VERSION 5.8 ;
BUSBITCHARS "[]" ;
DIVIDERCHAR "/" ;
UNITS
    DATABASE MICRONS 1000 ;
END UNITS

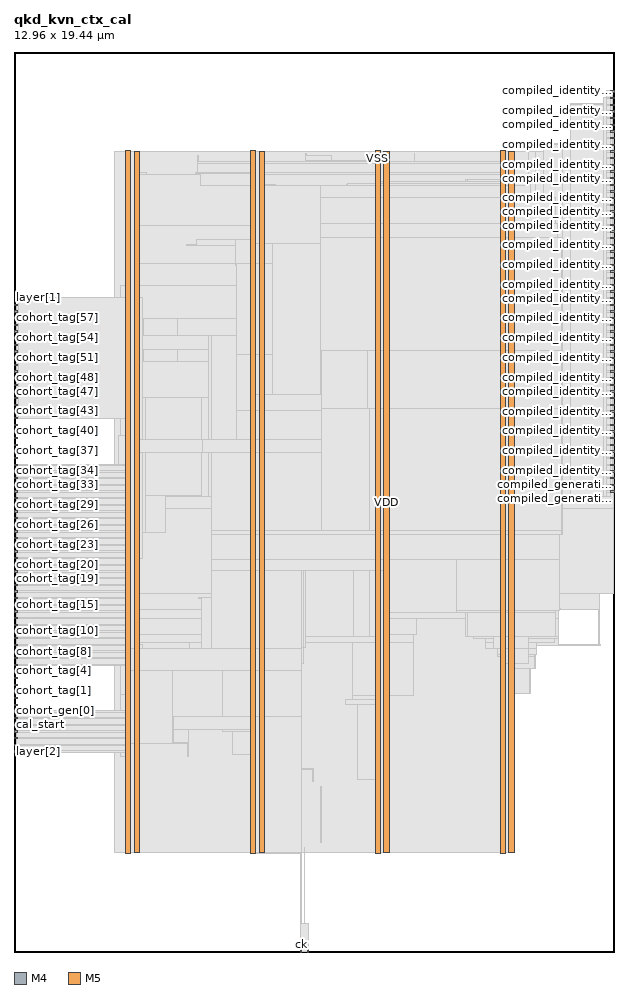
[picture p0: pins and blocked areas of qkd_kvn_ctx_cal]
MACRO qkd_kvn_ctx_cal
  FOREIGN qkd_kvn_ctx_cal 0 0 ;
  CLASS BLOCK ;
  SIZE 12.96 BY 19.44 ;
  PIN cal_start
    DIRECTION INPUT ;
    USE SIGNAL ;
    PORT
      LAYER M4 ;
        RECT  0 4.896 0.084 4.92 ;
    END
  END cal_start
  PIN ck
    DIRECTION INPUT ;
    USE SIGNAL ;
    PORT
      LAYER M5 ;
        RECT  6.192 0 6.216 0.084 ;
    END
  END ck
  PIN cohort_gen[0]
    DIRECTION INPUT ;
    USE SIGNAL ;
    PORT
      LAYER M4 ;
        RECT  0 5.04 0.084 5.064 ;
    END
  END cohort_gen[0]
  PIN cohort_gen[1]
    DIRECTION INPUT ;
    USE SIGNAL ;
    PORT
      LAYER M4 ;
        RECT  0 5.184 0.084 5.208 ;
    END
  END cohort_gen[1]
  PIN cohort_tag[0]
    DIRECTION INPUT ;
    USE SIGNAL ;
    PORT
      LAYER M4 ;
        RECT  0 5.328 0.084 5.352 ;
    END
  END cohort_tag[0]
  PIN cohort_tag[10]
    DIRECTION INPUT ;
    USE SIGNAL ;
    PORT
      LAYER M4 ;
        RECT  0 6.768 0.084 6.792 ;
    END
  END cohort_tag[10]
  PIN cohort_tag[11]
    DIRECTION INPUT ;
    USE SIGNAL ;
    PORT
      LAYER M4 ;
        RECT  0 6.912 0.084 6.936 ;
    END
  END cohort_tag[11]
  PIN cohort_tag[12]
    DIRECTION INPUT ;
    USE SIGNAL ;
    PORT
      LAYER M4 ;
        RECT  0 7.056 0.084 7.08 ;
    END
  END cohort_tag[12]
  PIN cohort_tag[13]
    DIRECTION INPUT ;
    USE SIGNAL ;
    PORT
      LAYER M4 ;
        RECT  0 7.2 0.084 7.224 ;
    END
  END cohort_tag[13]
  PIN cohort_tag[14]
    DIRECTION INPUT ;
    USE SIGNAL ;
    PORT
      LAYER M4 ;
        RECT  0 7.344 0.084 7.368 ;
    END
  END cohort_tag[14]
  PIN cohort_tag[15]
    DIRECTION INPUT ;
    USE SIGNAL ;
    PORT
      LAYER M4 ;
        RECT  0 7.488 0.084 7.512 ;
    END
  END cohort_tag[15]
  PIN cohort_tag[16]
    DIRECTION INPUT ;
    USE SIGNAL ;
    PORT
      LAYER M4 ;
        RECT  0 7.632 0.084 7.656 ;
    END
  END cohort_tag[16]
  PIN cohort_tag[17]
    DIRECTION INPUT ;
    USE SIGNAL ;
    PORT
      LAYER M4 ;
        RECT  0 7.776 0.084 7.8 ;
    END
  END cohort_tag[17]
  PIN cohort_tag[18]
    DIRECTION INPUT ;
    USE SIGNAL ;
    PORT
      LAYER M4 ;
        RECT  0 7.92 0.084 7.944 ;
    END
  END cohort_tag[18]
  PIN cohort_tag[19]
    DIRECTION INPUT ;
    USE SIGNAL ;
    PORT
      LAYER M4 ;
        RECT  0 8.064 0.084 8.088 ;
    END
  END cohort_tag[19]
  PIN cohort_tag[1]
    DIRECTION INPUT ;
    USE SIGNAL ;
    PORT
      LAYER M4 ;
        RECT  0 5.472 0.084 5.496 ;
    END
  END cohort_tag[1]
  PIN cohort_tag[20]
    DIRECTION INPUT ;
    USE SIGNAL ;
    PORT
      LAYER M4 ;
        RECT  0 8.208 0.084 8.232 ;
    END
  END cohort_tag[20]
  PIN cohort_tag[21]
    DIRECTION INPUT ;
    USE SIGNAL ;
    PORT
      LAYER M4 ;
        RECT  0 8.352 0.084 8.376 ;
    END
  END cohort_tag[21]
  PIN cohort_tag[22]
    DIRECTION INPUT ;
    USE SIGNAL ;
    PORT
      LAYER M4 ;
        RECT  0 8.496 0.084 8.52 ;
    END
  END cohort_tag[22]
  PIN cohort_tag[23]
    DIRECTION INPUT ;
    USE SIGNAL ;
    PORT
      LAYER M4 ;
        RECT  0 8.64 0.084 8.664 ;
    END
  END cohort_tag[23]
  PIN cohort_tag[24]
    DIRECTION INPUT ;
    USE SIGNAL ;
    PORT
      LAYER M4 ;
        RECT  0 8.784 0.084 8.808 ;
    END
  END cohort_tag[24]
  PIN cohort_tag[25]
    DIRECTION INPUT ;
    USE SIGNAL ;
    PORT
      LAYER M4 ;
        RECT  0 8.928 0.084 8.952 ;
    END
  END cohort_tag[25]
  PIN cohort_tag[26]
    DIRECTION INPUT ;
    USE SIGNAL ;
    PORT
      LAYER M4 ;
        RECT  0 9.072 0.084 9.096 ;
    END
  END cohort_tag[26]
  PIN cohort_tag[27]
    DIRECTION INPUT ;
    USE SIGNAL ;
    PORT
      LAYER M4 ;
        RECT  0 9.216 0.084 9.24 ;
    END
  END cohort_tag[27]
  PIN cohort_tag[28]
    DIRECTION INPUT ;
    USE SIGNAL ;
    PORT
      LAYER M4 ;
        RECT  0 9.36 0.084 9.384 ;
    END
  END cohort_tag[28]
  PIN cohort_tag[29]
    DIRECTION INPUT ;
    USE SIGNAL ;
    PORT
      LAYER M4 ;
        RECT  0 9.504 0.084 9.528 ;
    END
  END cohort_tag[29]
  PIN cohort_tag[2]
    DIRECTION INPUT ;
    USE SIGNAL ;
    PORT
      LAYER M4 ;
        RECT  0 5.616 0.084 5.64 ;
    END
  END cohort_tag[2]
  PIN cohort_tag[30]
    DIRECTION INPUT ;
    USE SIGNAL ;
    PORT
      LAYER M4 ;
        RECT  0 9.648 0.084 9.672 ;
    END
  END cohort_tag[30]
  PIN cohort_tag[31]
    DIRECTION INPUT ;
    USE SIGNAL ;
    PORT
      LAYER M4 ;
        RECT  0 9.792 0.084 9.816 ;
    END
  END cohort_tag[31]
  PIN cohort_tag[32]
    DIRECTION INPUT ;
    USE SIGNAL ;
    PORT
      LAYER M4 ;
        RECT  0 9.936 0.084 9.96 ;
    END
  END cohort_tag[32]
  PIN cohort_tag[33]
    DIRECTION INPUT ;
    USE SIGNAL ;
    PORT
      LAYER M4 ;
        RECT  0 10.08 0.084 10.104 ;
    END
  END cohort_tag[33]
  PIN cohort_tag[34]
    DIRECTION INPUT ;
    USE SIGNAL ;
    PORT
      LAYER M4 ;
        RECT  0 10.224 0.084 10.248 ;
    END
  END cohort_tag[34]
  PIN cohort_tag[35]
    DIRECTION INPUT ;
    USE SIGNAL ;
    PORT
      LAYER M4 ;
        RECT  0 10.368 0.084 10.392 ;
    END
  END cohort_tag[35]
  PIN cohort_tag[36]
    DIRECTION INPUT ;
    USE SIGNAL ;
    PORT
      LAYER M4 ;
        RECT  0 10.512 0.084 10.536 ;
    END
  END cohort_tag[36]
  PIN cohort_tag[37]
    DIRECTION INPUT ;
    USE SIGNAL ;
    PORT
      LAYER M4 ;
        RECT  0 10.656 0.084 10.68 ;
    END
  END cohort_tag[37]
  PIN cohort_tag[38]
    DIRECTION INPUT ;
    USE SIGNAL ;
    PORT
      LAYER M4 ;
        RECT  0 10.8 0.084 10.824 ;
    END
  END cohort_tag[38]
  PIN cohort_tag[39]
    DIRECTION INPUT ;
    USE SIGNAL ;
    PORT
      LAYER M4 ;
        RECT  0 10.944 0.084 10.968 ;
    END
  END cohort_tag[39]
  PIN cohort_tag[3]
    DIRECTION INPUT ;
    USE SIGNAL ;
    PORT
      LAYER M4 ;
        RECT  0 5.76 0.084 5.784 ;
    END
  END cohort_tag[3]
  PIN cohort_tag[40]
    DIRECTION INPUT ;
    USE SIGNAL ;
    PORT
      LAYER M4 ;
        RECT  0 11.088 0.084 11.112 ;
    END
  END cohort_tag[40]
  PIN cohort_tag[41]
    DIRECTION INPUT ;
    USE SIGNAL ;
    PORT
      LAYER M4 ;
        RECT  0 11.232 0.084 11.256 ;
    END
  END cohort_tag[41]
  PIN cohort_tag[42]
    DIRECTION INPUT ;
    USE SIGNAL ;
    PORT
      LAYER M4 ;
        RECT  0 11.376 0.084 11.4 ;
    END
  END cohort_tag[42]
  PIN cohort_tag[43]
    DIRECTION INPUT ;
    USE SIGNAL ;
    PORT
      LAYER M4 ;
        RECT  0 11.52 0.084 11.544 ;
    END
  END cohort_tag[43]
  PIN cohort_tag[44]
    DIRECTION INPUT ;
    USE SIGNAL ;
    PORT
      LAYER M4 ;
        RECT  0 11.664 0.084 11.688 ;
    END
  END cohort_tag[44]
  PIN cohort_tag[45]
    DIRECTION INPUT ;
    USE SIGNAL ;
    PORT
      LAYER M4 ;
        RECT  0 11.808 0.084 11.832 ;
    END
  END cohort_tag[45]
  PIN cohort_tag[46]
    DIRECTION INPUT ;
    USE SIGNAL ;
    PORT
      LAYER M4 ;
        RECT  0 11.952 0.084 11.976 ;
    END
  END cohort_tag[46]
  PIN cohort_tag[47]
    DIRECTION INPUT ;
    USE SIGNAL ;
    PORT
      LAYER M4 ;
        RECT  0 12.096 0.084 12.12 ;
    END
  END cohort_tag[47]
  PIN cohort_tag[48]
    DIRECTION INPUT ;
    USE SIGNAL ;
    PORT
      LAYER M4 ;
        RECT  0 12.24 0.084 12.264 ;
    END
  END cohort_tag[48]
  PIN cohort_tag[49]
    DIRECTION INPUT ;
    USE SIGNAL ;
    PORT
      LAYER M4 ;
        RECT  0 12.384 0.084 12.408 ;
    END
  END cohort_tag[49]
  PIN cohort_tag[4]
    DIRECTION INPUT ;
    USE SIGNAL ;
    PORT
      LAYER M4 ;
        RECT  0 5.904 0.084 5.928 ;
    END
  END cohort_tag[4]
  PIN cohort_tag[50]
    DIRECTION INPUT ;
    USE SIGNAL ;
    PORT
      LAYER M4 ;
        RECT  0 12.528 0.084 12.552 ;
    END
  END cohort_tag[50]
  PIN cohort_tag[51]
    DIRECTION INPUT ;
    USE SIGNAL ;
    PORT
      LAYER M4 ;
        RECT  0 12.672 0.084 12.696 ;
    END
  END cohort_tag[51]
  PIN cohort_tag[52]
    DIRECTION INPUT ;
    USE SIGNAL ;
    PORT
      LAYER M4 ;
        RECT  0 12.816 0.084 12.84 ;
    END
  END cohort_tag[52]
  PIN cohort_tag[53]
    DIRECTION INPUT ;
    USE SIGNAL ;
    PORT
      LAYER M4 ;
        RECT  0 12.96 0.084 12.984 ;
    END
  END cohort_tag[53]
  PIN cohort_tag[54]
    DIRECTION INPUT ;
    USE SIGNAL ;
    PORT
      LAYER M4 ;
        RECT  0 13.104 0.084 13.128 ;
    END
  END cohort_tag[54]
  PIN cohort_tag[55]
    DIRECTION INPUT ;
    USE SIGNAL ;
    PORT
      LAYER M4 ;
        RECT  0 13.248 0.084 13.272 ;
    END
  END cohort_tag[55]
  PIN cohort_tag[56]
    DIRECTION INPUT ;
    USE SIGNAL ;
    PORT
      LAYER M4 ;
        RECT  0 13.392 0.084 13.416 ;
    END
  END cohort_tag[56]
  PIN cohort_tag[57]
    DIRECTION INPUT ;
    USE SIGNAL ;
    PORT
      LAYER M4 ;
        RECT  0 13.536 0.084 13.56 ;
    END
  END cohort_tag[57]
  PIN cohort_tag[58]
    DIRECTION INPUT ;
    USE SIGNAL ;
    PORT
      LAYER M4 ;
        RECT  0 13.68 0.084 13.704 ;
    END
  END cohort_tag[58]
  PIN cohort_tag[5]
    DIRECTION INPUT ;
    USE SIGNAL ;
    PORT
      LAYER M4 ;
        RECT  0 6.048 0.084 6.072 ;
    END
  END cohort_tag[5]
  PIN cohort_tag[6]
    DIRECTION INPUT ;
    USE SIGNAL ;
    PORT
      LAYER M4 ;
        RECT  0 6.192 0.084 6.216 ;
    END
  END cohort_tag[6]
  PIN cohort_tag[7]
    DIRECTION INPUT ;
    USE SIGNAL ;
    PORT
      LAYER M4 ;
        RECT  0 6.336 0.084 6.36 ;
    END
  END cohort_tag[7]
  PIN cohort_tag[8]
    DIRECTION INPUT ;
    USE SIGNAL ;
    PORT
      LAYER M4 ;
        RECT  0 6.48 0.084 6.504 ;
    END
  END cohort_tag[8]
  PIN cohort_tag[9]
    DIRECTION INPUT ;
    USE SIGNAL ;
    PORT
      LAYER M4 ;
        RECT  0 6.624 0.084 6.648 ;
    END
  END cohort_tag[9]
  PIN compiled_generation[0]
    DIRECTION OUTPUT ;
    USE SIGNAL ;
    PORT
      LAYER M4 ;
        RECT  12.876 9.936 12.96 9.96 ;
    END
  END compiled_generation[0]
  PIN compiled_generation[1]
    DIRECTION OUTPUT ;
    USE SIGNAL ;
    PORT
      LAYER M4 ;
        RECT  12.876 10.08 12.96 10.104 ;
    END
  END compiled_generation[1]
  PIN compiled_identity[0]
    DIRECTION OUTPUT ;
    USE SIGNAL ;
    PORT
      LAYER M4 ;
        RECT  12.876 10.224 12.96 10.248 ;
    END
  END compiled_identity[0]
  PIN compiled_identity[10]
    DIRECTION OUTPUT ;
    USE SIGNAL ;
    PORT
      LAYER M4 ;
        RECT  12.876 11.664 12.96 11.688 ;
    END
  END compiled_identity[10]
  PIN compiled_identity[11]
    DIRECTION OUTPUT ;
    USE SIGNAL ;
    PORT
      LAYER M4 ;
        RECT  12.876 11.808 12.96 11.832 ;
    END
  END compiled_identity[11]
  PIN compiled_identity[12]
    DIRECTION OUTPUT ;
    USE SIGNAL ;
    PORT
      LAYER M4 ;
        RECT  12.876 11.952 12.96 11.976 ;
    END
  END compiled_identity[12]
  PIN compiled_identity[13]
    DIRECTION OUTPUT ;
    USE SIGNAL ;
    PORT
      LAYER M4 ;
        RECT  12.876 12.096 12.96 12.12 ;
    END
  END compiled_identity[13]
  PIN compiled_identity[14]
    DIRECTION OUTPUT ;
    USE SIGNAL ;
    PORT
      LAYER M4 ;
        RECT  12.876 12.24 12.96 12.264 ;
    END
  END compiled_identity[14]
  PIN compiled_identity[15]
    DIRECTION OUTPUT ;
    USE SIGNAL ;
    PORT
      LAYER M4 ;
        RECT  12.876 12.384 12.96 12.408 ;
    END
  END compiled_identity[15]
  PIN compiled_identity[16]
    DIRECTION OUTPUT ;
    USE SIGNAL ;
    PORT
      LAYER M4 ;
        RECT  12.876 12.528 12.96 12.552 ;
    END
  END compiled_identity[16]
  PIN compiled_identity[17]
    DIRECTION OUTPUT ;
    USE SIGNAL ;
    PORT
      LAYER M4 ;
        RECT  12.876 12.672 12.96 12.696 ;
    END
  END compiled_identity[17]
  PIN compiled_identity[18]
    DIRECTION OUTPUT ;
    USE SIGNAL ;
    PORT
      LAYER M4 ;
        RECT  12.876 12.816 12.96 12.84 ;
    END
  END compiled_identity[18]
  PIN compiled_identity[19]
    DIRECTION OUTPUT ;
    USE SIGNAL ;
    PORT
      LAYER M4 ;
        RECT  12.876 12.96 12.96 12.984 ;
    END
  END compiled_identity[19]
  PIN compiled_identity[1]
    DIRECTION OUTPUT ;
    USE SIGNAL ;
    PORT
      LAYER M4 ;
        RECT  12.876 10.368 12.96 10.392 ;
    END
  END compiled_identity[1]
  PIN compiled_identity[20]
    DIRECTION OUTPUT ;
    USE SIGNAL ;
    PORT
      LAYER M4 ;
        RECT  12.876 13.104 12.96 13.128 ;
    END
  END compiled_identity[20]
  PIN compiled_identity[21]
    DIRECTION OUTPUT ;
    USE SIGNAL ;
    PORT
      LAYER M4 ;
        RECT  12.876 13.248 12.96 13.272 ;
    END
  END compiled_identity[21]
  PIN compiled_identity[22]
    DIRECTION OUTPUT ;
    USE SIGNAL ;
    PORT
      LAYER M4 ;
        RECT  12.876 13.392 12.96 13.416 ;
    END
  END compiled_identity[22]
  PIN compiled_identity[23]
    DIRECTION OUTPUT ;
    USE SIGNAL ;
    PORT
      LAYER M4 ;
        RECT  12.876 13.536 12.96 13.56 ;
    END
  END compiled_identity[23]
  PIN compiled_identity[24]
    DIRECTION OUTPUT ;
    USE SIGNAL ;
    PORT
      LAYER M4 ;
        RECT  12.876 13.68 12.96 13.704 ;
    END
  END compiled_identity[24]
  PIN compiled_identity[25]
    DIRECTION OUTPUT ;
    USE SIGNAL ;
    PORT
      LAYER M4 ;
        RECT  12.876 13.824 12.96 13.848 ;
    END
  END compiled_identity[25]
  PIN compiled_identity[26]
    DIRECTION OUTPUT ;
    USE SIGNAL ;
    PORT
      LAYER M4 ;
        RECT  12.876 13.968 12.96 13.992 ;
    END
  END compiled_identity[26]
  PIN compiled_identity[27]
    DIRECTION OUTPUT ;
    USE SIGNAL ;
    PORT
      LAYER M4 ;
        RECT  12.876 14.112 12.96 14.136 ;
    END
  END compiled_identity[27]
  PIN compiled_identity[28]
    DIRECTION OUTPUT ;
    USE SIGNAL ;
    PORT
      LAYER M4 ;
        RECT  12.876 14.256 12.96 14.28 ;
    END
  END compiled_identity[28]
  PIN compiled_identity[29]
    DIRECTION OUTPUT ;
    USE SIGNAL ;
    PORT
      LAYER M4 ;
        RECT  12.876 14.4 12.96 14.424 ;
    END
  END compiled_identity[29]
  PIN compiled_identity[2]
    DIRECTION OUTPUT ;
    USE SIGNAL ;
    PORT
      LAYER M4 ;
        RECT  12.876 10.512 12.96 10.536 ;
    END
  END compiled_identity[2]
  PIN compiled_identity[30]
    DIRECTION OUTPUT ;
    USE SIGNAL ;
    PORT
      LAYER M4 ;
        RECT  12.876 14.544 12.96 14.568 ;
    END
  END compiled_identity[30]
  PIN compiled_identity[31]
    DIRECTION OUTPUT ;
    USE SIGNAL ;
    PORT
      LAYER M4 ;
        RECT  12.876 14.688 12.96 14.712 ;
    END
  END compiled_identity[31]
  PIN compiled_identity[32]
    DIRECTION OUTPUT ;
    USE SIGNAL ;
    PORT
      LAYER M4 ;
        RECT  12.876 14.832 12.96 14.856 ;
    END
  END compiled_identity[32]
  PIN compiled_identity[33]
    DIRECTION OUTPUT ;
    USE SIGNAL ;
    PORT
      LAYER M4 ;
        RECT  12.876 14.976 12.96 15 ;
    END
  END compiled_identity[33]
  PIN compiled_identity[34]
    DIRECTION OUTPUT ;
    USE SIGNAL ;
    PORT
      LAYER M4 ;
        RECT  12.876 15.12 12.96 15.144 ;
    END
  END compiled_identity[34]
  PIN compiled_identity[35]
    DIRECTION OUTPUT ;
    USE SIGNAL ;
    PORT
      LAYER M4 ;
        RECT  12.876 15.264 12.96 15.288 ;
    END
  END compiled_identity[35]
  PIN compiled_identity[36]
    DIRECTION OUTPUT ;
    USE SIGNAL ;
    PORT
      LAYER M4 ;
        RECT  12.876 15.408 12.96 15.432 ;
    END
  END compiled_identity[36]
  PIN compiled_identity[37]
    DIRECTION OUTPUT ;
    USE SIGNAL ;
    PORT
      LAYER M4 ;
        RECT  12.876 15.552 12.96 15.576 ;
    END
  END compiled_identity[37]
  PIN compiled_identity[38]
    DIRECTION OUTPUT ;
    USE SIGNAL ;
    PORT
      LAYER M4 ;
        RECT  12.876 15.696 12.96 15.72 ;
    END
  END compiled_identity[38]
  PIN compiled_identity[39]
    DIRECTION OUTPUT ;
    USE SIGNAL ;
    PORT
      LAYER M4 ;
        RECT  12.876 15.84 12.96 15.864 ;
    END
  END compiled_identity[39]
  PIN compiled_identity[3]
    DIRECTION OUTPUT ;
    USE SIGNAL ;
    PORT
      LAYER M4 ;
        RECT  12.876 10.656 12.96 10.68 ;
    END
  END compiled_identity[3]
  PIN compiled_identity[40]
    DIRECTION OUTPUT ;
    USE SIGNAL ;
    PORT
      LAYER M4 ;
        RECT  12.876 15.984 12.96 16.008 ;
    END
  END compiled_identity[40]
  PIN compiled_identity[41]
    DIRECTION OUTPUT ;
    USE SIGNAL ;
    PORT
      LAYER M4 ;
        RECT  12.876 16.128 12.96 16.152 ;
    END
  END compiled_identity[41]
  PIN compiled_identity[42]
    DIRECTION OUTPUT ;
    USE SIGNAL ;
    PORT
      LAYER M4 ;
        RECT  12.876 16.272 12.96 16.296 ;
    END
  END compiled_identity[42]
  PIN compiled_identity[43]
    DIRECTION OUTPUT ;
    USE SIGNAL ;
    PORT
      LAYER M4 ;
        RECT  12.876 16.416 12.96 16.44 ;
    END
  END compiled_identity[43]
  PIN compiled_identity[44]
    DIRECTION OUTPUT ;
    USE SIGNAL ;
    PORT
      LAYER M4 ;
        RECT  12.876 16.56 12.96 16.584 ;
    END
  END compiled_identity[44]
  PIN compiled_identity[45]
    DIRECTION OUTPUT ;
    USE SIGNAL ;
    PORT
      LAYER M4 ;
        RECT  12.876 16.704 12.96 16.728 ;
    END
  END compiled_identity[45]
  PIN compiled_identity[46]
    DIRECTION OUTPUT ;
    USE SIGNAL ;
    PORT
      LAYER M4 ;
        RECT  12.876 16.848 12.96 16.872 ;
    END
  END compiled_identity[46]
  PIN compiled_identity[47]
    DIRECTION OUTPUT ;
    USE SIGNAL ;
    PORT
      LAYER M4 ;
        RECT  12.876 16.992 12.96 17.016 ;
    END
  END compiled_identity[47]
  PIN compiled_identity[48]
    DIRECTION OUTPUT ;
    USE SIGNAL ;
    PORT
      LAYER M4 ;
        RECT  12.876 17.136 12.96 17.16 ;
    END
  END compiled_identity[48]
  PIN compiled_identity[49]
    DIRECTION OUTPUT ;
    USE SIGNAL ;
    PORT
      LAYER M4 ;
        RECT  12.876 17.28 12.96 17.304 ;
    END
  END compiled_identity[49]
  PIN compiled_identity[4]
    DIRECTION OUTPUT ;
    USE SIGNAL ;
    PORT
      LAYER M4 ;
        RECT  12.876 10.8 12.96 10.824 ;
    END
  END compiled_identity[4]
  PIN compiled_identity[50]
    DIRECTION OUTPUT ;
    USE SIGNAL ;
    PORT
      LAYER M4 ;
        RECT  12.876 17.424 12.96 17.448 ;
    END
  END compiled_identity[50]
  PIN compiled_identity[51]
    DIRECTION OUTPUT ;
    USE SIGNAL ;
    PORT
      LAYER M4 ;
        RECT  12.876 17.568 12.96 17.592 ;
    END
  END compiled_identity[51]
  PIN compiled_identity[52]
    DIRECTION OUTPUT ;
    USE SIGNAL ;
    PORT
      LAYER M4 ;
        RECT  12.876 17.712 12.96 17.736 ;
    END
  END compiled_identity[52]
  PIN compiled_identity[53]
    DIRECTION OUTPUT ;
    USE SIGNAL ;
    PORT
      LAYER M4 ;
        RECT  12.876 17.856 12.96 17.88 ;
    END
  END compiled_identity[53]
  PIN compiled_identity[54]
    DIRECTION OUTPUT ;
    USE SIGNAL ;
    PORT
      LAYER M4 ;
        RECT  12.876 18 12.96 18.024 ;
    END
  END compiled_identity[54]
  PIN compiled_identity[55]
    DIRECTION OUTPUT ;
    USE SIGNAL ;
    PORT
      LAYER M4 ;
        RECT  12.876 18.144 12.96 18.168 ;
    END
  END compiled_identity[55]
  PIN compiled_identity[56]
    DIRECTION OUTPUT ;
    USE SIGNAL ;
    PORT
      LAYER M4 ;
        RECT  12.876 18.288 12.96 18.312 ;
    END
  END compiled_identity[56]
  PIN compiled_identity[57]
    DIRECTION OUTPUT ;
    USE SIGNAL ;
    PORT
      LAYER M4 ;
        RECT  12.876 18.432 12.96 18.456 ;
    END
  END compiled_identity[57]
  PIN compiled_identity[58]
    DIRECTION OUTPUT ;
    USE SIGNAL ;
    PORT
      LAYER M4 ;
        RECT  12.876 18.576 12.96 18.6 ;
    END
  END compiled_identity[58]
  PIN compiled_identity[5]
    DIRECTION OUTPUT ;
    USE SIGNAL ;
    PORT
      LAYER M4 ;
        RECT  12.876 10.944 12.96 10.968 ;
    END
  END compiled_identity[5]
  PIN compiled_identity[6]
    DIRECTION OUTPUT ;
    USE SIGNAL ;
    PORT
      LAYER M4 ;
        RECT  12.876 11.088 12.96 11.112 ;
    END
  END compiled_identity[6]
  PIN compiled_identity[7]
    DIRECTION OUTPUT ;
    USE SIGNAL ;
    PORT
      LAYER M4 ;
        RECT  12.876 11.232 12.96 11.256 ;
    END
  END compiled_identity[7]
  PIN compiled_identity[8]
    DIRECTION OUTPUT ;
    USE SIGNAL ;
    PORT
      LAYER M4 ;
        RECT  12.876 11.376 12.96 11.4 ;
    END
  END compiled_identity[8]
  PIN compiled_identity[9]
    DIRECTION OUTPUT ;
    USE SIGNAL ;
    PORT
      LAYER M4 ;
        RECT  12.876 11.52 12.96 11.544 ;
    END
  END compiled_identity[9]
  PIN layer[0]
    DIRECTION INPUT ;
    USE SIGNAL ;
    PORT
      LAYER M4 ;
        RECT  0 13.824 0.084 13.848 ;
    END
  END layer[0]
  PIN layer[1]
    DIRECTION INPUT ;
    USE SIGNAL ;
    PORT
      LAYER M4 ;
        RECT  0 13.968 0.084 13.992 ;
    END
  END layer[1]
  PIN layer[2]
    DIRECTION INPUT ;
    USE SIGNAL ;
    PORT
      LAYER M4 ;
        RECT  0 4.32 0.084 4.344 ;
    END
  END layer[2]
  PIN layer[3]
    DIRECTION INPUT ;
    USE SIGNAL ;
    PORT
      LAYER M4 ;
        RECT  0 4.464 0.084 4.488 ;
    END
  END layer[3]
  PIN layer[4]
    DIRECTION INPUT ;
    USE SIGNAL ;
    PORT
      LAYER M4 ;
        RECT  0 4.608 0.084 4.632 ;
    END
  END layer[4]
  PIN layer[5]
    DIRECTION INPUT ;
    USE SIGNAL ;
    PORT
      LAYER M4 ;
        RECT  0 4.752 0.084 4.776 ;
    END
  END layer[5]
  PIN rst_n
    DIRECTION INPUT ;
    USE SIGNAL ;
    PORT
      LAYER M5 ;
        RECT  6.336 0 6.36 0.084 ;
    END
  END rst_n
  PIN VDD
    DIRECTION INOUT ;
    USE POWER ;
    PORT
      LAYER M5 ;
        RECT  10.692 2.151 10.812 17.289 ;
        RECT  7.992 2.151 8.112 17.289 ;
        RECT  5.292 2.151 5.412 17.289 ;
        RECT  2.592 2.151 2.712 17.289 ;
    END
  END VDD
  PIN VSS
    DIRECTION INOUT ;
    USE GROUND ;
    PORT
      LAYER M5 ;
        RECT  10.5 2.137 10.62 17.303 ;
        RECT  7.8 2.137 7.92 17.303 ;
        RECT  5.1 2.137 5.22 17.303 ;
        RECT  2.4 2.137 2.52 17.303 ;
    END
  END VSS
  # OT_OBS_CLOSED layer=M5 d_um=1.536 added=9
  OBS
    LAYER RVTN ;
     RECT  2.16 2.16 10.8 2.295 ;
     RECT  2.16 2.565 10.8 2.835 ;
     RECT  2.16 3.105 10.8 3.375 ;
     RECT  2.16 3.645 10.8 3.915 ;
     RECT  2.16 4.185 10.8 4.455 ;
     RECT  2.16 4.725 10.8 4.995 ;
     RECT  2.16 5.265 10.8 5.535 ;
     RECT  2.16 5.805 10.8 6.075 ;
     RECT  2.16 6.345 10.8 6.615 ;
     RECT  2.16 6.885 10.8 7.155 ;
     RECT  2.16 7.425 10.8 7.695 ;
     RECT  2.16 7.965 10.8 8.235 ;
     RECT  2.16 8.505 10.8 8.775 ;
     RECT  2.16 9.045 10.8 9.315 ;
     RECT  2.16 9.585 10.8 9.855 ;
     RECT  2.16 10.125 10.8 10.395 ;
     RECT  2.16 10.665 10.8 10.935 ;
     RECT  2.16 11.205 10.8 11.475 ;
     RECT  2.16 11.745 10.8 12.015 ;
     RECT  2.16 12.285 10.8 12.555 ;
     RECT  2.16 12.825 10.8 13.095 ;
     RECT  2.16 13.365 10.8 13.635 ;
     RECT  2.16 13.905 10.8 14.175 ;
     RECT  2.16 14.445 10.8 14.715 ;
     RECT  2.16 14.985 10.8 15.255 ;
     RECT  2.16 15.525 10.8 15.795 ;
     RECT  2.16 16.065 10.8 16.335 ;
     RECT  2.16 16.605 10.8 16.875 ;
     RECT  2.16 17.145 10.8 17.28 ;
    LAYER RVTP ;
     RECT  2.16 2.295 10.8 2.565 ;
     RECT  2.16 2.835 10.8 3.105 ;
     RECT  2.16 3.375 10.8 3.645 ;
     RECT  2.16 3.915 10.8 4.185 ;
     RECT  2.16 4.455 10.8 4.725 ;
     RECT  2.16 4.995 10.8 5.265 ;
     RECT  2.16 5.535 10.8 5.805 ;
     RECT  2.16 6.075 10.8 6.345 ;
     RECT  2.16 6.615 10.8 6.885 ;
     RECT  2.16 7.155 10.8 7.425 ;
     RECT  2.16 7.695 10.8 7.965 ;
     RECT  2.16 8.235 10.8 8.505 ;
     RECT  2.16 8.775 10.8 9.045 ;
     RECT  2.16 9.315 10.8 9.585 ;
     RECT  2.16 9.855 10.8 10.125 ;
     RECT  2.16 10.395 10.8 10.665 ;
     RECT  2.16 10.935 10.8 11.205 ;
     RECT  2.16 11.475 10.8 11.745 ;
     RECT  2.16 12.015 10.8 12.285 ;
     RECT  2.16 12.555 10.8 12.825 ;
     RECT  2.16 13.095 10.8 13.365 ;
     RECT  2.16 13.635 10.8 13.905 ;
     RECT  2.16 14.175 10.8 14.445 ;
     RECT  2.16 14.715 10.8 14.985 ;
     RECT  2.16 15.255 10.8 15.525 ;
     RECT  2.16 15.795 10.8 16.065 ;
     RECT  2.16 16.335 10.8 16.605 ;
     RECT  2.16 16.875 10.8 17.145 ;
    LAYER M1 ;
     RECT  2.16 2.151 10.8 17.289 ;
    LAYER M2 ;
     RECT  0.535 4.5 2.16 4.518 ;
     RECT  0.103 12.528 2.16 12.546 ;
     RECT  2.16 2.151 10.8 17.289 ;
     RECT  10.8 2.421 10.812 17.019 ;
     RECT  10.812 15.426 10.859 16.362 ;
     RECT  10.812 13.068 10.931 14.634 ;
     RECT  10.812 5.58 10.967 11.664 ;
     RECT  10.931 14.346 11.003 14.634 ;
     RECT  10.967 5.58 11.147 11.304 ;
     RECT  11.147 6.12 11.255 11.304 ;
     RECT  11.255 6.426 11.291 11.304 ;
     RECT  10.931 13.068 11.579 13.086 ;
     RECT  11.291 6.624 11.759 11.304 ;
     RECT  11.759 7.398 11.831 11.304 ;
     RECT  11.003 14.346 11.975 14.364 ;
     RECT  11.831 7.398 12.011 11.034 ;
     RECT  10.859 15.696 12.011 16.362 ;
     RECT  12.011 16.344 12.047 16.362 ;
     RECT  12.011 7.74 12.587 11.034 ;
     RECT  11.759 6.624 12.659 6.642 ;
     RECT  12.587 9.018 12.695 11.034 ;
     RECT  12.695 11.016 12.731 11.034 ;
     RECT  12.631 12.528 12.739 12.546 ;
     RECT  12.695 9.018 12.767 10.224 ;
     RECT  12.739 12.456 12.767 12.546 ;
     RECT  12.767 12.456 12.775 12.474 ;
     RECT  12.379 13.41 12.775 13.428 ;
     RECT  12.767 9.018 12.803 9.414 ;
     RECT  12.803 9.324 12.839 9.414 ;
     RECT  12.775 12.024 12.839 12.474 ;
     RECT  12.811 17.928 12.847 17.946 ;
     RECT  12.767 10.206 12.875 10.224 ;
     RECT  12.839 12.024 12.875 12.042 ;
     RECT  12.839 9.324 12.911 9.342 ;
     RECT  12.775 13.338 12.911 13.428 ;
     RECT  12.847 17.694 12.911 17.946 ;
     RECT  12.587 7.74 12.947 7.758 ;
     RECT  12.911 17.694 12.947 17.712 ;
    LAYER M3 ;
     RECT  6.264 0.571 6.282 2.255 ;
     RECT  2.415 2.143 2.505 2.413 ;
     RECT  5.115 2.143 5.205 2.413 ;
     RECT  7.815 2.143 7.905 2.413 ;
     RECT  10.515 2.143 10.605 2.413 ;
     RECT  6.624 2.371 6.642 3.569 ;
     RECT  7.815 2.413 8.097 3.721 ;
     RECT  6.444 3.685 6.462 3.965 ;
     RECT  2.415 2.413 2.697 4.225 ;
     RECT  5.115 2.413 5.397 4.261 ;
     RECT  2.304 4.225 2.697 4.531 ;
     RECT  3.744 4.225 3.762 4.531 ;
     RECT  0.54 4.495 0.558 4.637 ;
     RECT  4.716 4.261 5.397 4.765 ;
     RECT  2.304 4.531 3.762 4.801 ;
     RECT  4.5 4.765 5.397 4.801 ;
     RECT  6.192 4.621 6.21 4.801 ;
     RECT  7.416 3.721 8.097 5.341 ;
     RECT  7.164 5.341 8.097 5.459 ;
     RECT  7.308 5.459 8.097 5.539 ;
     RECT  2.304 4.801 6.21 5.567 ;
     RECT  10.515 2.413 10.797 5.575 ;
     RECT  10.515 5.575 11.142 6.115 ;
     RECT  4.716 5.567 6.21 6.241 ;
     RECT  10.515 6.115 11.25 6.385 ;
     RECT  10.44 6.385 11.25 6.421 ;
     RECT  10.44 6.421 11.286 6.547 ;
     RECT  4.716 6.241 6.246 6.571 ;
     RECT  2.304 5.567 3.798 6.691 ;
     RECT  4.716 6.571 6.282 6.691 ;
     RECT  7.308 5.539 8.622 6.691 ;
     RECT  10.188 6.547 11.286 6.691 ;
     RECT  10.188 6.691 11.682 6.781 ;
     RECT  9.936 6.781 11.754 6.808 ;
     RECT  2.304 6.691 8.622 6.853 ;
     RECT  2.304 6.853 8.694 7.195 ;
     RECT  9.756 6.808 11.754 7.195 ;
     RECT  2.304 7.195 11.754 7.393 ;
     RECT  12.636 6.619 12.654 7.393 ;
     RECT  2.304 7.393 12.654 7.735 ;
     RECT  2.304 7.735 12.942 9.589 ;
     RECT  2.268 9.589 12.942 11.165 ;
     RECT  0.108 12.523 0.126 12.56 ;
     RECT  2.304 11.165 12.942 12.749 ;
     RECT  0.144 13.531 0.162 13.661 ;
     RECT  2.304 12.749 2.79 13.675 ;
     RECT  3.528 12.749 12.942 13.675 ;
     RECT  0.108 13.963 0.126 14.141 ;
     RECT  2.304 13.675 12.942 14.405 ;
     RECT  2.415 14.405 12.942 14.861 ;
     RECT  2.415 14.861 11.826 15.691 ;
     RECT  12.6 14.861 12.942 15.691 ;
     RECT  2.415 15.691 12.942 16.799 ;
     RECT  2.415 16.799 2.862 16.835 ;
     RECT  3.924 16.799 12.942 16.835 ;
     RECT  2.415 16.835 2.697 17.027 ;
     RECT  3.96 16.835 12.942 17.027 ;
     RECT  3.96 17.027 10.605 17.069 ;
     RECT  6.3 17.069 7.905 17.105 ;
     RECT  3.96 17.069 3.978 17.213 ;
     RECT  6.3 17.105 6.858 17.213 ;
     RECT  6.3 17.213 6.318 17.249 ;
     RECT  8.64 17.069 8.658 17.249 ;
     RECT  2.415 17.027 2.505 17.297 ;
     RECT  5.115 17.069 5.205 17.297 ;
     RECT  7.815 17.105 7.905 17.297 ;
     RECT  10.515 17.069 10.605 17.297 ;
     RECT  11.448 17.027 12.942 17.453 ;
     RECT  12.024 17.453 12.942 17.717 ;
     RECT  12.024 17.717 12.906 17.951 ;
     RECT  12.024 17.951 12.834 18.317 ;
     RECT  12.744 18.317 12.834 18.461 ;
     RECT  12.816 18.461 12.834 18.605 ;
    LAYER M4 ;
     RECT  0.084 11.52 0.097 11.544 ;
     RECT  0.06 11.544 0.097 11.664 ;
     RECT  0.084 11.664 0.097 11.688 ;
     RECT  0.06 11.688 0.097 11.808 ;
     RECT  0.084 11.808 0.097 11.832 ;
     RECT  0.06 11.832 0.097 11.952 ;
     RECT  0.084 11.952 0.097 11.976 ;
     RECT  0.06 11.976 0.097 12.096 ;
     RECT  0.084 12.096 0.097 12.12 ;
     RECT  0.06 12.12 0.097 12.24 ;
     RECT  0.084 12.24 0.097 12.264 ;
     RECT  0.06 12.264 0.097 12.384 ;
     RECT  0.084 12.384 0.097 12.408 ;
     RECT  0.06 12.408 0.097 12.528 ;
     RECT  0.084 12.528 0.097 12.552 ;
     RECT  0.06 12.552 0.097 12.672 ;
     RECT  0.084 12.672 0.097 12.696 ;
     RECT  0.06 12.696 0.097 12.816 ;
     RECT  0.084 12.816 0.097 12.84 ;
     RECT  0.06 12.84 0.097 12.96 ;
     RECT  0.084 12.96 0.097 12.984 ;
     RECT  0.06 12.984 0.097 13.104 ;
     RECT  0.084 13.104 0.097 13.128 ;
     RECT  0.06 13.128 0.097 13.248 ;
     RECT  0.084 13.248 0.097 13.272 ;
     RECT  0.06 13.272 0.097 13.392 ;
     RECT  0.084 13.392 0.097 13.416 ;
     RECT  0.06 13.416 0.097 13.536 ;
     RECT  0.084 13.536 0.097 13.56 ;
     RECT  0.06 13.56 0.097 13.68 ;
     RECT  0.084 13.68 0.097 13.704 ;
     RECT  0.06 13.704 0.097 13.824 ;
     RECT  0.084 13.824 0.097 13.848 ;
     RECT  0.06 13.848 0.097 13.968 ;
     RECT  0.084 13.968 0.097 13.992 ;
     RECT  0.084 4.32 2.408 4.344 ;
     RECT  0.06 4.344 2.408 4.464 ;
     RECT  0.084 4.464 2.408 4.488 ;
     RECT  0.06 4.488 2.408 4.608 ;
     RECT  0.084 4.608 2.408 4.632 ;
     RECT  0.06 4.632 2.408 4.752 ;
     RECT  0.084 4.752 2.408 4.776 ;
     RECT  0.06 4.776 2.408 4.896 ;
     RECT  0.084 4.896 2.408 4.92 ;
     RECT  0.06 4.92 2.408 5.04 ;
     RECT  0.084 5.04 2.408 5.064 ;
     RECT  0.06 5.064 2.408 5.184 ;
     RECT  0.084 5.184 2.408 5.208 ;
     RECT  0.084 6.192 2.408 6.216 ;
     RECT  0.06 6.216 2.408 6.336 ;
     RECT  0.084 6.336 2.408 6.36 ;
     RECT  0.06 6.36 2.408 6.48 ;
     RECT  0.084 6.48 2.408 6.504 ;
     RECT  0.06 6.504 2.408 6.624 ;
     RECT  0.084 6.624 2.408 6.648 ;
     RECT  0.06 6.648 2.408 6.768 ;
     RECT  0.084 6.768 2.408 6.792 ;
     RECT  0.06 6.792 2.408 6.912 ;
     RECT  0.084 6.912 2.408 6.936 ;
     RECT  0.06 6.936 2.408 7.056 ;
     RECT  0.084 7.056 2.408 7.08 ;
     RECT  0.06 7.08 2.408 7.2 ;
     RECT  0.084 7.2 2.408 7.224 ;
     RECT  0.06 7.224 2.408 7.344 ;
     RECT  0.084 7.344 2.408 7.368 ;
     RECT  0.06 7.368 2.408 7.488 ;
     RECT  0.084 7.488 2.408 7.512 ;
     RECT  0.06 7.512 2.408 7.632 ;
     RECT  0.084 7.632 2.408 7.656 ;
     RECT  0.06 7.656 2.408 7.776 ;
     RECT  0.084 7.776 2.408 7.8 ;
     RECT  0.06 7.8 2.408 7.92 ;
     RECT  0.084 7.92 2.408 7.944 ;
     RECT  0.06 7.944 2.408 8.064 ;
     RECT  0.084 8.064 2.408 8.088 ;
     RECT  0.06 8.088 2.408 8.208 ;
     RECT  0.084 8.208 2.408 8.232 ;
     RECT  0.06 8.232 2.408 8.352 ;
     RECT  0.084 8.352 2.408 8.376 ;
     RECT  0.06 8.376 2.408 8.496 ;
     RECT  0.084 8.496 2.408 8.52 ;
     RECT  0.06 8.52 2.408 8.64 ;
     RECT  0.084 8.64 2.408 8.664 ;
     RECT  0.06 8.664 2.408 8.784 ;
     RECT  0.084 8.784 2.408 8.808 ;
     RECT  0.06 8.808 2.408 8.928 ;
     RECT  0.084 8.928 2.408 8.952 ;
     RECT  0.06 8.952 2.408 9.072 ;
     RECT  0.084 9.072 2.408 9.096 ;
     RECT  0.06 9.096 2.408 9.216 ;
     RECT  0.084 9.216 2.408 9.24 ;
     RECT  0.06 9.24 2.408 9.36 ;
     RECT  0.084 9.36 2.408 9.384 ;
     RECT  0.06 9.384 2.408 9.504 ;
     RECT  0.084 9.504 2.408 9.528 ;
     RECT  0.06 9.528 2.408 9.648 ;
     RECT  0.084 9.648 2.408 9.672 ;
     RECT  0.06 9.672 2.408 9.792 ;
     RECT  0.084 9.792 2.408 9.816 ;
     RECT  0.06 9.816 2.408 9.936 ;
     RECT  0.084 9.936 2.408 9.96 ;
     RECT  0.06 9.96 2.408 10.08 ;
     RECT  0.084 10.08 2.408 10.104 ;
     RECT  0.06 10.104 2.408 10.224 ;
     RECT  0.084 10.224 2.408 10.248 ;
     RECT  0.06 10.248 2.408 10.368 ;
     RECT  0.084 10.368 2.408 10.392 ;
     RECT  0.06 10.392 2.408 10.512 ;
     RECT  0.084 10.512 2.408 10.536 ;
     RECT  0.097 11.52 2.408 14.136 ;
     RECT  2.408 2.148 2.512 17.292 ;
     RECT  2.512 2.418 2.704 17.022 ;
     RECT  2.704 4.512 2.765 6.648 ;
     RECT  2.704 8.496 2.765 14.136 ;
     RECT  2.765 9.072 2.837 11.976 ;
     RECT  2.837 9.072 3.269 9.864 ;
     RECT  2.765 4.512 3.443 6.552 ;
     RECT  3.443 4.512 3.773 4.536 ;
     RECT  3.733 15.264 3.949 15.288 ;
     RECT  3.913 16.8 4.021 16.824 ;
     RECT  3.443 5.952 4.057 6.552 ;
     RECT  3.985 7.632 4.057 7.656 ;
     RECT  3.269 9.84 4.057 9.864 ;
     RECT  2.837 10.848 4.057 11.976 ;
     RECT  4.057 9.84 4.201 11.976 ;
     RECT  2.765 13.008 4.201 13.32 ;
     RECT  4.201 9.84 4.261 13.32 ;
     RECT  4.057 5.952 4.489 7.656 ;
     RECT  3.949 15.264 4.777 15.384 ;
     RECT  4.261 8.688 4.885 13.32 ;
     RECT  4.489 5.088 5.108 7.656 ;
     RECT  4.885 8.688 5.108 13.656 ;
     RECT  4.777 14.832 5.108 15.384 ;
     RECT  4.021 16.56 5.108 16.824 ;
     RECT  5.108 2.148 5.212 17.292 ;
     RECT  5.212 2.418 5.404 17.022 ;
     RECT  5.404 6.096 5.645 16.584 ;
     RECT  5.645 6.096 5.825 16.44 ;
     RECT  5.404 3.936 5.939 4.92 ;
     RECT  5.825 6.336 6.005 16.44 ;
     RECT  6.005 6.576 6.257 16.44 ;
     RECT  6.257 6.576 6.293 14.232 ;
     RECT  6.253 0.576 6.371 0.6 ;
     RECT  5.939 3.936 6.473 3.96 ;
     RECT  6.257 15.264 6.613 16.44 ;
     RECT  6.613 15.264 7.189 16.536 ;
     RECT  6.293 6.816 7.333 9.672 ;
     RECT  6.293 11.76 7.333 14.232 ;
     RECT  7.189 15.264 7.333 16.584 ;
     RECT  7.333 6.816 7.669 10.2 ;
     RECT  7.333 11.76 7.669 16.584 ;
     RECT  7.669 6.816 7.808 16.584 ;
     RECT  7.808 2.148 7.912 17.292 ;
     RECT  7.912 2.418 8.104 17.022 ;
     RECT  8.104 8.496 8.309 12.6 ;
     RECT  8.104 14.592 8.597 16.632 ;
     RECT  8.309 12.528 9.133 12.6 ;
     RECT  9.133 12.528 9.205 12.984 ;
     RECT  8.309 8.496 9.395 11.4 ;
     RECT  9.205 12.528 9.397 13.08 ;
     RECT  9.395 11.184 9.497 11.4 ;
     RECT  9.497 11.376 9.673 11.4 ;
     RECT  9.397 12.528 9.673 13.896 ;
     RECT  9.541 7.344 9.701 7.368 ;
     RECT  9.395 8.496 9.701 9.864 ;
     RECT  8.597 15.504 9.701 16.632 ;
     RECT  9.701 7.344 9.745 9.864 ;
     RECT  9.701 15.408 9.745 16.632 ;
     RECT  9.673 11.376 9.845 13.896 ;
     RECT  9.745 6.816 10.357 9.864 ;
     RECT  10.357 6.576 10.429 9.864 ;
     RECT  10.429 6.576 10.508 10.2 ;
     RECT  9.845 11.376 10.508 14.28 ;
     RECT  9.745 15.408 10.508 16.68 ;
     RECT  10.508 2.148 10.612 17.292 ;
     RECT  10.612 2.418 10.804 17.292 ;
     RECT  10.804 6.24 11.123 17.292 ;
     RECT  11.123 6.816 11.267 17.292 ;
     RECT  11.267 9.024 11.437 17.292 ;
     RECT  11.267 6.816 11.699 7.944 ;
     RECT  11.699 7.392 11.747 7.944 ;
     RECT  11.747 7.392 11.795 7.416 ;
     RECT  11.437 9.024 11.843 17.448 ;
     RECT  11.843 9.84 12.013 17.448 ;
     RECT  12.013 9.84 12.733 18.312 ;
     RECT  12.733 9.84 12.805 18.456 ;
     RECT  12.805 9.84 12.881 9.936 ;
     RECT  12.805 9.936 12.876 9.96 ;
     RECT  12.805 9.96 12.881 10.08 ;
     RECT  12.805 10.08 12.876 10.104 ;
     RECT  12.805 10.104 12.881 10.224 ;
     RECT  12.805 10.224 12.876 10.248 ;
     RECT  12.805 10.248 12.881 10.368 ;
     RECT  12.805 10.368 12.876 10.392 ;
     RECT  12.805 10.392 12.881 10.512 ;
     RECT  12.805 10.512 12.876 10.536 ;
     RECT  12.805 10.536 12.881 10.656 ;
     RECT  12.805 10.656 12.876 10.68 ;
     RECT  12.805 10.68 12.881 10.8 ;
     RECT  12.805 10.8 12.876 10.824 ;
     RECT  12.805 10.824 12.881 10.944 ;
     RECT  12.805 10.944 12.876 10.968 ;
     RECT  12.805 10.968 12.881 11.088 ;
     RECT  12.805 11.088 12.876 11.112 ;
     RECT  12.805 11.112 12.881 11.232 ;
     RECT  12.805 11.232 12.876 11.256 ;
     RECT  12.805 11.256 12.881 11.376 ;
     RECT  12.805 11.376 12.876 11.4 ;
     RECT  12.805 11.4 12.881 11.52 ;
     RECT  12.805 11.52 12.876 11.544 ;
     RECT  12.805 11.544 12.881 11.664 ;
     RECT  12.805 11.664 12.876 11.688 ;
     RECT  12.805 11.688 12.881 11.808 ;
     RECT  12.805 11.808 12.876 11.832 ;
     RECT  12.805 11.832 12.881 11.952 ;
     RECT  12.805 11.952 12.876 11.976 ;
     RECT  12.805 11.976 12.881 12.096 ;
     RECT  12.805 12.096 12.876 12.12 ;
     RECT  12.805 12.12 12.881 12.24 ;
     RECT  12.805 12.24 12.876 12.264 ;
     RECT  12.805 12.264 12.881 12.384 ;
     RECT  12.805 12.384 12.876 12.408 ;
     RECT  12.805 12.408 12.881 12.528 ;
     RECT  12.805 12.528 12.876 12.552 ;
     RECT  12.805 12.552 12.881 12.672 ;
     RECT  12.805 12.672 12.876 12.696 ;
     RECT  12.805 12.696 12.881 12.816 ;
     RECT  12.805 12.816 12.876 12.84 ;
     RECT  12.805 12.84 12.881 12.96 ;
     RECT  12.805 12.96 12.876 12.984 ;
     RECT  12.805 12.984 12.881 13.104 ;
     RECT  12.805 13.104 12.876 13.128 ;
     RECT  12.805 13.128 12.881 13.248 ;
     RECT  12.805 13.248 12.876 13.272 ;
     RECT  12.805 13.272 12.881 13.392 ;
     RECT  12.805 13.392 12.876 13.416 ;
     RECT  12.805 13.416 12.881 13.536 ;
     RECT  12.805 13.536 12.876 13.56 ;
     RECT  12.805 13.56 12.881 13.68 ;
     RECT  12.805 13.68 12.876 13.704 ;
     RECT  12.805 13.704 12.881 13.824 ;
     RECT  12.805 13.824 12.876 13.848 ;
     RECT  12.805 13.848 12.881 13.968 ;
     RECT  12.805 13.968 12.876 13.992 ;
     RECT  12.805 13.992 12.881 14.112 ;
     RECT  12.805 14.112 12.876 14.136 ;
     RECT  12.805 14.136 12.881 14.256 ;
     RECT  12.805 14.256 12.876 14.28 ;
     RECT  12.805 14.28 12.881 14.4 ;
     RECT  12.805 14.4 12.876 14.424 ;
     RECT  12.805 14.424 12.881 14.544 ;
     RECT  12.805 14.544 12.876 14.568 ;
     RECT  12.805 14.568 12.881 14.688 ;
     RECT  12.805 14.688 12.876 14.712 ;
     RECT  12.805 14.712 12.881 14.832 ;
     RECT  12.805 14.832 12.876 14.856 ;
     RECT  12.805 14.856 12.881 14.976 ;
     RECT  12.805 14.976 12.876 15 ;
     RECT  12.805 15 12.881 15.12 ;
     RECT  12.805 15.12 12.876 15.144 ;
     RECT  12.805 15.144 12.881 15.264 ;
     RECT  12.805 15.264 12.876 15.288 ;
     RECT  12.805 15.288 12.881 15.408 ;
     RECT  12.805 15.408 12.876 15.432 ;
     RECT  12.805 15.432 12.881 15.552 ;
     RECT  12.805 15.552 12.876 15.576 ;
     RECT  12.805 15.576 12.881 15.696 ;
     RECT  12.805 15.696 12.876 15.72 ;
     RECT  12.805 15.72 12.881 15.84 ;
     RECT  12.805 15.84 12.876 15.864 ;
     RECT  12.805 15.864 12.881 15.984 ;
     RECT  12.805 15.984 12.876 16.008 ;
     RECT  12.805 16.008 12.881 16.128 ;
     RECT  12.805 16.128 12.876 16.152 ;
     RECT  12.805 16.152 12.881 16.272 ;
     RECT  12.805 16.272 12.876 16.296 ;
     RECT  12.805 16.296 12.881 16.416 ;
     RECT  12.805 16.416 12.876 16.44 ;
     RECT  12.805 16.44 12.881 16.56 ;
     RECT  12.805 16.56 12.876 16.584 ;
     RECT  12.805 16.584 12.881 16.704 ;
     RECT  12.805 16.704 12.876 16.728 ;
     RECT  12.805 16.728 12.881 16.848 ;
     RECT  12.805 16.848 12.876 16.872 ;
     RECT  12.805 16.872 12.881 16.992 ;
     RECT  12.805 16.992 12.876 17.016 ;
     RECT  12.805 17.016 12.881 17.136 ;
     RECT  12.805 17.136 12.876 17.16 ;
     RECT  12.805 17.16 12.881 17.28 ;
     RECT  12.805 17.28 12.876 17.304 ;
     RECT  12.805 17.304 12.881 17.424 ;
     RECT  12.805 17.424 12.876 17.448 ;
     RECT  12.805 17.448 12.881 17.568 ;
     RECT  12.805 17.568 12.876 17.592 ;
     RECT  12.805 17.592 12.881 17.712 ;
     RECT  12.805 17.712 12.876 17.736 ;
     RECT  12.805 17.736 12.881 17.856 ;
     RECT  12.805 17.856 12.876 17.88 ;
     RECT  12.805 17.88 12.881 18 ;
     RECT  12.805 18 12.876 18.024 ;
     RECT  12.805 18.024 12.881 18.144 ;
     RECT  12.805 18.144 12.876 18.168 ;
     RECT  12.805 18.168 12.881 18.288 ;
     RECT  12.805 18.288 12.876 18.312 ;
     RECT  12.805 18.312 12.881 18.432 ;
     RECT  12.805 18.432 12.876 18.456 ;
     RECT  12.805 18.456 12.881 18.576 ;
     RECT  12.805 18.576 12.876 18.6 ;
     RECT  12.881 9.96 12.924 10.08 ;
     RECT  12.881 10.104 12.924 10.224 ;
     RECT  12.881 10.248 12.924 10.368 ;
     RECT  12.881 10.392 12.924 10.512 ;
     RECT  12.881 10.536 12.924 10.656 ;
     RECT  12.881 10.68 12.924 10.8 ;
     RECT  12.881 10.824 12.924 10.944 ;
     RECT  12.881 10.968 12.924 11.088 ;
     RECT  12.881 11.112 12.924 11.232 ;
     RECT  12.881 11.256 12.924 11.376 ;
     RECT  12.881 11.4 12.924 11.52 ;
     RECT  12.881 11.544 12.924 11.664 ;
     RECT  12.881 11.688 12.924 11.808 ;
     RECT  12.881 11.832 12.924 11.952 ;
     RECT  12.881 11.976 12.924 12.096 ;
     RECT  12.881 12.12 12.924 12.24 ;
     RECT  12.881 12.264 12.924 12.384 ;
     RECT  12.881 12.408 12.924 12.528 ;
     RECT  12.881 12.552 12.924 12.672 ;
     RECT  12.881 12.696 12.924 12.816 ;
     RECT  12.881 12.84 12.924 12.96 ;
     RECT  12.881 12.984 12.924 13.104 ;
     RECT  12.881 13.128 12.924 13.248 ;
     RECT  12.881 13.272 12.924 13.392 ;
     RECT  12.881 13.416 12.924 13.536 ;
     RECT  12.881 13.56 12.924 13.68 ;
     RECT  12.881 13.704 12.924 13.824 ;
     RECT  12.881 13.848 12.924 13.968 ;
     RECT  12.881 13.992 12.924 14.112 ;
     RECT  12.881 14.136 12.924 14.256 ;
     RECT  12.881 14.28 12.924 14.4 ;
     RECT  12.881 14.424 12.924 14.544 ;
     RECT  12.881 14.568 12.924 14.688 ;
     RECT  12.881 14.712 12.924 14.832 ;
     RECT  12.881 14.856 12.924 14.976 ;
     RECT  12.881 15 12.924 15.12 ;
     RECT  12.881 15.144 12.924 15.264 ;
     RECT  12.881 15.288 12.924 15.408 ;
     RECT  12.881 15.432 12.924 15.552 ;
     RECT  12.881 15.576 12.924 15.696 ;
     RECT  12.881 15.72 12.924 15.84 ;
     RECT  12.881 15.864 12.924 15.984 ;
     RECT  12.881 16.008 12.924 16.128 ;
     RECT  12.881 16.152 12.924 16.272 ;
     RECT  12.881 16.296 12.924 16.416 ;
     RECT  12.881 16.44 12.924 16.56 ;
     RECT  12.881 16.584 12.924 16.704 ;
     RECT  12.881 16.728 12.924 16.848 ;
     RECT  12.881 16.872 12.924 16.992 ;
     RECT  12.881 17.016 12.924 17.136 ;
     RECT  12.881 17.16 12.924 17.28 ;
     RECT  12.881 17.304 12.924 17.424 ;
     RECT  12.881 17.448 12.924 17.568 ;
     RECT  12.881 17.592 12.924 17.712 ;
     RECT  12.881 17.736 12.924 17.856 ;
     RECT  12.881 17.88 12.924 18 ;
     RECT  12.881 18.024 12.924 18.144 ;
     RECT  12.881 18.168 12.924 18.288 ;
     RECT  12.881 18.312 12.924 18.432 ;
     RECT  12.881 18.456 12.924 18.576 ;
    LAYER M5 ;
     RECT  6.216 0.016 6.336 0.084 ;
     RECT  6.192 0.084 6.36 0.611 ;
     RECT  2.4 2.137 2.52 2.151 ;
     RECT  5.1 2.137 5.22 2.151 ;
     RECT  6.192 0.611 6.216 2.151 ;
     RECT  7.8 2.137 7.92 2.151 ;
     RECT  10.5 2.137 10.62 2.151 ;
     RECT  2.4 2.151 2.712 4.501 ;
     RECT  5.1 2.151 6.216 5.077 ;
     RECT  2.4 4.501 3.432 6.085 ;
     RECT  4.512 5.077 6.216 6.085 ;
     RECT  10.5 2.151 10.812 6.229 ;
     RECT  2.4 6.085 6.216 6.563 ;
     RECT  10.5 6.229 11.112 6.565 ;
     RECT  10.368 6.565 11.112 6.805 ;
     RECT  9.792 6.805 11.688 7.333 ;
     RECT  9.552 7.333 11.688 7.381 ;
     RECT  4.272 6.563 6.216 8.245 ;
     RECT  7.8 2.151 8.112 8.245 ;
     RECT  4.272 8.245 8.112 8.485 ;
     RECT  9.552 7.381 11.784 8.485 ;
     RECT  4.272 8.485 11.784 9.013 ;
     RECT  4.272 9.013 11.832 9.107 ;
     RECT  4.272 9.107 6.648 10.789 ;
     RECT  4.08 10.789 6.648 11.075 ;
     RECT  4.8 11.075 6.648 11.699 ;
     RECT  7.68 9.107 11.832 11.749 ;
     RECT  5.1 11.699 6.648 12.035 ;
     RECT  5.1 12.035 5.592 12.901 ;
     RECT  6.624 12.035 6.648 12.997 ;
     RECT  7.632 11.749 11.832 12.997 ;
     RECT  4.8 12.901 5.592 14.867 ;
     RECT  5.1 14.867 5.592 15.299 ;
     RECT  6.624 12.997 11.832 15.443 ;
     RECT  6.624 15.443 11.736 15.731 ;
     RECT  6.624 15.731 11.688 16.307 ;
     RECT  6.624 16.307 11.16 16.547 ;
     RECT  7.2 16.547 11.16 16.595 ;
     RECT  7.8 16.595 10.812 16.643 ;
     RECT  9.792 16.643 10.812 16.691 ;
     RECT  2.4 6.563 2.712 17.289 ;
     RECT  5.1 15.299 5.412 17.289 ;
     RECT  7.8 16.643 8.112 17.289 ;
     RECT  10.5 16.691 10.812 17.289 ;
     RECT  2.4 17.289 2.52 17.303 ;
     RECT  5.1 17.289 5.22 17.303 ;
     RECT  7.8 17.289 7.92 17.303 ;
     RECT  10.5 17.289 10.62 17.303 ;
     RECT  5.22 2.137 6.192 2.151 ;
     RECT  3.432 5.077 4.512 6.085 ;
     RECT  8.112 7.333 9.552 8.485 ;
     RECT  6.648 9.107 7.68 11.749 ;
     RECT  2.712 10.789 4.08 11.075 ;
     RECT  4.8 11.699 5.1 12.901 ;
     RECT  6.648 11.749 7.632 12.997 ;
     RECT  5.592 12.035 6.624 15.299 ;
     RECT  5.412 15.299 6.624 16.547 ;
  END
END qkd_kvn_ctx_cal
END LIBRARY
